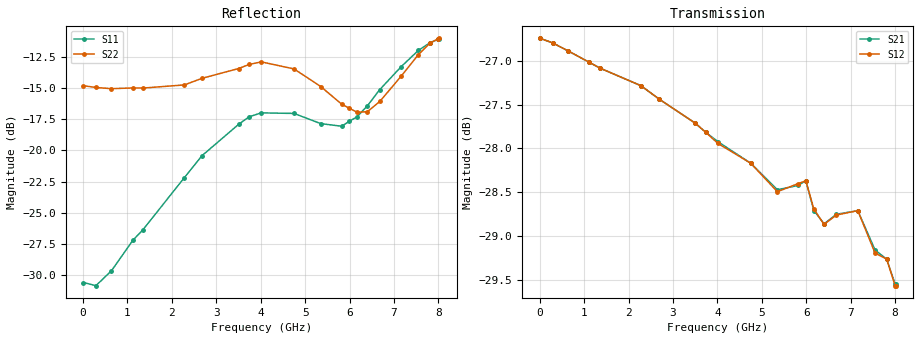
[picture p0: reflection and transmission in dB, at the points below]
! DEVICE ID: PE43712
! File Path: z:\PE43713\PE43713_CHAR_NOM_04292014\AMB\3p300\LS_ATT_25p50dB\PE43713_AMB_3p300V_3p000V_0p000V_LS_ATT_25p50dB_S2P_SN_10_A0139A.s2p
! Serial: 10
! Lot: A0139A
! Temp: 25C
! VDD: 3.300
! VSS: 0.000
! Control_Hi: 3.000
! Control_Lo: 0.000
! Attenuation Step: 25.50dB
! Port 1: RF1
! Port 2: RF2
! ThroughPath:1-2
! IDD: 0.0001452278
! ISS: -1.046e-007
#  Hz  S  RI  R  50
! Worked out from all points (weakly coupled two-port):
!   801 points, 10 MHz to 8.01 GHz, reference 50 ohm
!   highest |S21| = -26.75 dB at 10 MHz (marker M1); lowest = -29.6 dB at 8 GHz (marker M2)
!   lowest |S11| = -30.9 dB at 290 MHz (marker M3), VSWR 1.06, Z = 47.4 + j1.03 ohm
!   |S11| at or under -10 dB: start of sweep to end of sweep
!   |S22| runs from -17.0 to -11.0 dB; largest |S21 - S12| = 0.00018
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1e7  -0.0295 0.000798  0.046 -0.000217  0.046 -0.000204  -0.1818 0.00131
2.9e8  -0.0265 0.0109  0.0455 -0.00458  0.0455 -0.00459  -0.1777 0.0204
6.4e8  -0.0234 0.0231  0.0442 -0.00967  0.0442 -0.00969  -0.1715 0.0433
1.12e9  -0.0179 0.0397  0.0416 -0.016  0.0416 -0.016  -0.1618 0.0744
1.35e9  -0.0133 0.0462  0.0401 -0.0187  0.0401 -0.0187  -0.155 0.0873
2.28e9  0.0131 0.0766  0.0325 -0.0285  0.0325 -0.0285  -0.1155 0.1421
2.68e9  0.0267 0.0915  0.0284 -0.0316  0.0284 -0.0316  -0.0943 0.1703
3.5e9  0.0458 0.1186  0.0192 -0.0364  0.0192 -0.0364  -0.0627 0.2036
3.74e9  0.0496 0.1271  0.0164 -0.0372  0.0164 -0.0372  -0.0578 0.2135
4.01e9  0.0534 0.131  0.0133 -0.0379  0.0133 -0.0378  -0.054 0.2201
4.75e9  0.0636 0.1255  0.00515 -0.0387  0.00515 -0.0387  -0.0318 0.2099
5.35e9  0.0803 0.0998  -0.000723 -0.0377  -0.000744 -0.0376  -0.0109 0.1801
5.82e9  0.1012 0.0734  -0.00562 -0.0375  -0.00558 -0.0376  0.0259 0.1512
5.99e9  0.113 0.0657  -0.00806 -0.0373  -0.00801 -0.0373  0.043 0.1413
6.17e9  0.1241 0.0568  -0.01 -0.0353  -0.00993 -0.0354  0.0629 0.1275
6.4e9  0.1424 0.0503  -0.0108 -0.0344  -0.0107 -0.0344  0.0904 0.1108
6.68e9  0.1699 0.0436  -0.0133 -0.034  -0.0132 -0.034  0.1251 0.0951
7.16e9  0.213 0.0397  -0.0188 -0.0315  -0.0188 -0.0315  0.1787 0.0863
7.55e9  0.2484 0.0433  -0.0215 -0.0274  -0.0214 -0.0273  0.2252 0.0898
7.81e9  0.2659 0.0481  -0.0229 -0.0257  -0.0229 -0.0257  0.2522 0.0952
8e9  0.2746 0.0515  -0.0232 -0.0239  -0.0231 -0.0239  0.2643 0.0955
8.01e9  0.275 0.0521  -0.0232 -0.0239  -0.0231 -0.0239  0.2649 0.0954
